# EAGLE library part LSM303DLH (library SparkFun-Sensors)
I2C accelerometer/magnetometer/tilt compensated compass

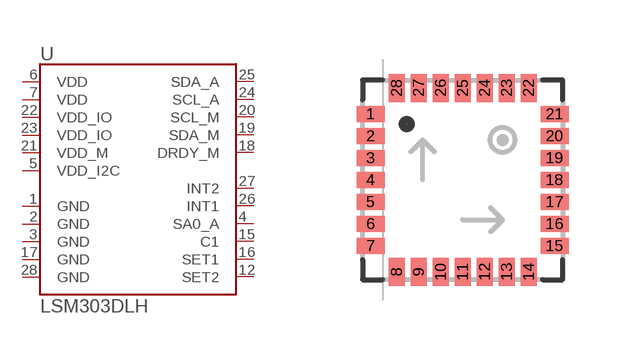
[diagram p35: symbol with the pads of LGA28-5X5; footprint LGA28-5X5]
Designator prefix U

## LSM303DLHSMD  [LGA28-5X5]
1  GND
2  GND
3  GND
4  SA0_A
5  VDD_I2C
6  VDD
7  VDD
12  SET2
15  C1
16  SET1
17  GND
18  DRDY_M
19  SDA_M
20  SCL_M
21  VDD_M
22  VDD_IO
23  VDD_IO
24  SCL_A
25  SDA_A
26  INT1
27  INT2
28  GND

## Footprint LGA28-5X5 (pad centres in mm)
smd 0.7 x 0.4: 1 -2.3,1.65; 2 -2.3,1.1; 3 -2.3,0.55; 4 -2.3,0; 5 -2.3,-0.55; 6 -2.3,-1.1; 7 -2.3,-1.65; 15 2.3,-1.65; 16 2.3,-1.1; 17 2.3,-0.55; 18 2.3,0; 19 2.3,0.55; 20 2.3,1.1; 21 2.3,1.65
smd 0.4 x 0.7: 8 -1.65,-2.3; 9 -1.1,-2.3; 10 -0.55,-2.3; 11 0,-2.3; 12 0.55,-2.3; 13 1.1,-2.3; 14 1.65,-2.3; 22 1.65,2.3; 23 1.1,2.3; 24 0.55,2.3; 25 0,2.3; 26 -0.55,2.3; 27 -1.1,2.3; 28 -1.65,2.3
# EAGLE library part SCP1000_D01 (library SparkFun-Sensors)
Barometric pressure sensor. Schematic elements and footprint production proven. Spark Fun Electronics SKU : COM-08128

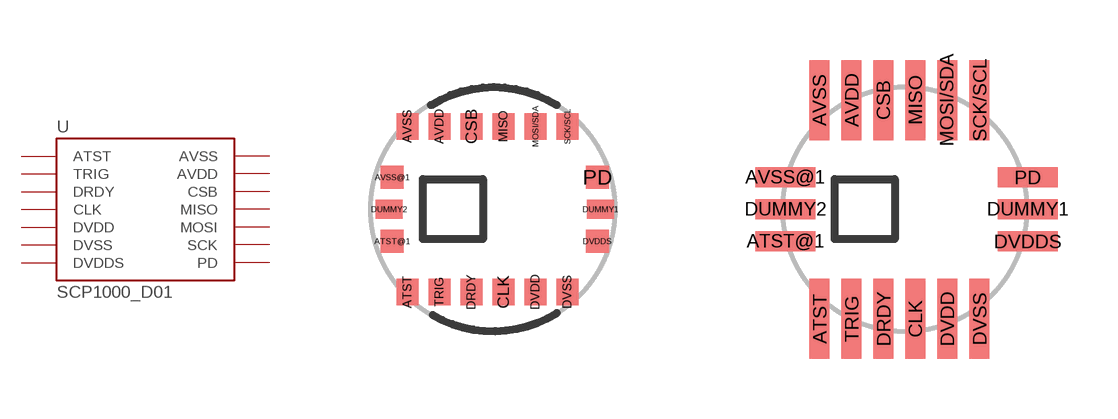
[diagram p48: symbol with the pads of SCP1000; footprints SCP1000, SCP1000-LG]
Designator prefix U

## SCP1000_D01SMD  [SCP1000]
ATST  ATST
AVDD  AVDD
AVSS  AVSS
CLK  CLK
CSB  CSB
DRDY  DRDY
DVDD  DVDD
DVDDS  DVDDS
DVSS  DVSS
MISO  MISO
MOSI/SDA  MOSI
PD  PD
SCK/SCL  SCK
TRIG  TRIG

## SCP1000_D01SMD2  [SCP1000-LG]
Pads as for SCP1000

## Footprint SCP1000 (pad centres in mm)
smd 0.55 x 0.67: ATST -2.135,-2.07; AVDD -1.335,2.07; AVSS -2.135,2.07; CLK 0.265,-2.07; CSB -0.535,2.07; DRDY -0.535,-2.07; DVDD 1.065,-2.07; DVSS 1.865,-2.07; MISO 0.265,2.07; MOSI/SDA 1.065,2.07; SCK/SCL 1.865,2.07; TRIG -1.335,-2.07
smd 0.57 x 0.57: ATST@1 -2.515,-0.8; AVSS@1 -2.515,0.8; DVDDS 2.615,-0.8; PD 2.615,0.8
smd 0.67 x 0.47: DUMMY1 2.695,0; DUMMY2 -2.595,0

## Footprint SCP1000-LG (pad centres in mm)
smd 0.5 x 2: ATST -2.13,-2.74; AVDD -1.33,2.73; AVSS -2.14,2.73; CLK 0.26,-2.74; CSB -0.54,2.73; DRDY -0.53,-2.74; DVDD 1.06,-2.74; DVSS 1.87,-2.74; MISO 0.26,2.73; MOSI/SDA 1.06,2.73; SCK/SCL 1.87,2.73; TRIG -1.33,-2.74
smd 1.5 x 0.5: ATST@1 -2.98,-0.8; AVSS@1 -2.99,0.8; DUMMY1 3.08,0; DUMMY2 -2.98,0; DVDDS 3.08,-0.8; PD 3.08,0.8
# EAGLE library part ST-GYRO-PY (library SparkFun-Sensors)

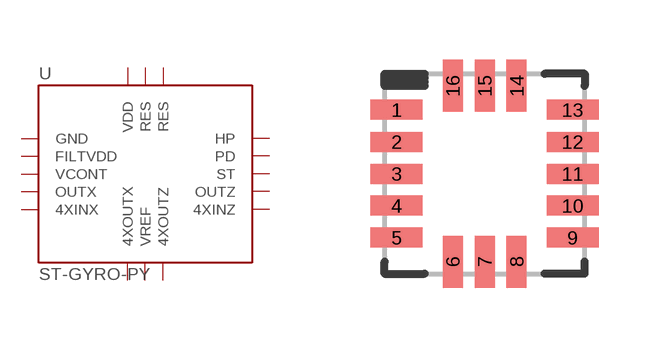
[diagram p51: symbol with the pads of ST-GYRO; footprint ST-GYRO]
Designator prefix -

## ST-GYRO-PYSMD  [ST-GYRO]
1  GND
2  FILTVDD
3  VCONT
4  OUTX
5  4XINX
6  4XOUTX
7  VREF
8  4XOUTZ
9  4XINZ
10  OUTZ
11  ST
12  PD
13  HP
14  RES
15  RES
16  VDD

## Footprint ST-GYRO (pad centres in mm)
smd 1.3 x 0.5: 1 -2.2,1.6; 2 -2.2,0.8; 3 -2.2,0; 4 -2.2,-0.8; 5 -2.2,-1.6; 9 2.2,-1.6; 10 2.2,-0.8; 11 2.2,0; 12 2.2,0.8; 13 2.2,1.6
smd 0.5 x 1.3: 6 -0.8,-2.2; 7 0,-2.2; 8 0.8,-2.2; 14 0.8,2.2; 15 0,2.2; 16 -0.8,2.2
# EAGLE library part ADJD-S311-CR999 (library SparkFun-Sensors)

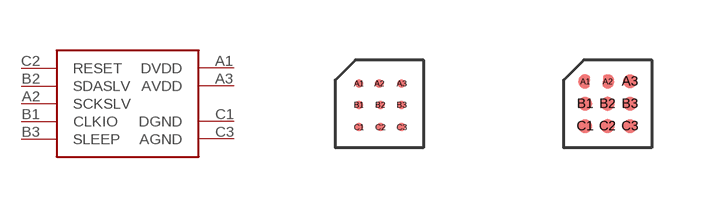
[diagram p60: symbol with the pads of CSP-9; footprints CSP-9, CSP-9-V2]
Designator prefix -

## ADJD-S311-CR999  [CSP-9]
A1  DVDD
A2  SCKSLV
A3  AVDD
B1  CLKIO
B2  SDASLV
B3  SLEEP
C1  DGND
C2  RESET
C3  AGND

## ADJD-S311-CR999V2  [CSP-9-V2]
Pads as for CSP-9

## Footprint CSP-9 (pad centres in mm)
smd 0.21 x 0.21: A1 -0.509,0.509; A2 0,0.509; A3 0.56,0.509; B1 -0.509,-0.025; B2 0.025,-0.025; B3 0.56,-0.025; C1 -0.509,-0.585; C2 0.025,-0.585; C3 0.56,-0.585

## Footprint CSP-9-V2 (pad centres in mm)
smd 0.152 x 0.152: A1 -0.56,0.56; A2 0,0.56
smd 0.356 x 0.356: A3 0.56,0.56; B1 -0.56,0; B2 0,0; B3 0.56,0; C1 -0.56,-0.56; C2 0,-0.56; C3 0.56,-0.56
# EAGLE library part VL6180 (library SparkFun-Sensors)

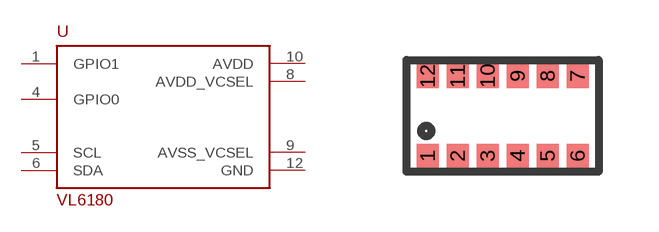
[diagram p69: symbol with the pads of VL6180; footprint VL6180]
Designator prefix U

## VL6180 (PROD_ID: IC-12007)  [VL6180]
1  GPIO1
4  GPIO0
5  SCL
6  SDA
8  AVDD_VCSEL
9  AVSS_VCSEL
10  AVDD
12  GND

## Footprint VL6180 (pad centres in mm)
smd 0.55 x 0.6: 1 -1.875,-1; 2 -1.125,-1; 3 -0.375,-1; 4 0.375,-1; 5 1.125,-1; 6 1.875,-1; 7 1.875,1; 8 1.125,1; 9 0.375,1; 10 -0.375,1; 11 -1.125,1; 12 -1.875,1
